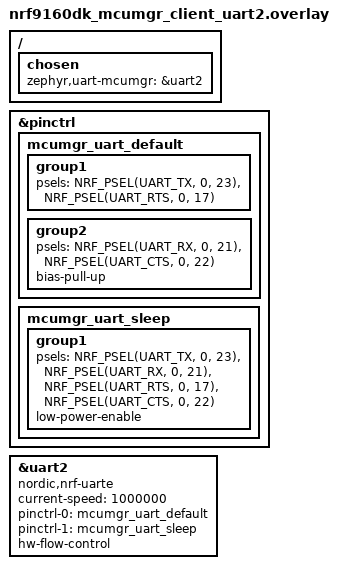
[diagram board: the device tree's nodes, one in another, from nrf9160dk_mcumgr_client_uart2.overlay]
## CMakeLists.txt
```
#
# Copyright (c) 2025 Nordic Semiconductor
#
# SPDX-License-Identifier: LicenseRef-Nordic-5-Clause
#

cmake_minimum_required(VERSION 3.20.0)

find_package(Zephyr REQUIRED HINTS $ENV{ZEPHYR_BASE})
project(nrf_cloud_fota_sample)

# NORDIC SDK APP START
target_sources(app PRIVATE src/main.c)
# NORDIC SDK APP END
```

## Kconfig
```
#
# Copyright (c) 2025 Nordic Semiconductor ASA
#
# SPDX-License-Identifier: LicenseRef-Nordic-5-Clause
#

menu "nRF Cloud CoAP FOTA Sample"

config COAP_FOTA_JOB_CHECK_RATE_MINUTES
	int "Rate (minutes) at which this sample will check for FOTA updates"
	range 1 10080
	default 15

config COAP_FOTA_LTE_LED_NUM
	int "LED number to use for LTE connection status"
	default 0

config COAP_FOTA_BUTTON_EVT_NUM
	int "Button number to use for device interactions"
	default 1

module = NRF_CLOUD_COAP_FOTA_SAMPLE
module-str = nRF Cloud CoAP FOTA Sample
source "${ZEPHYR_BASE}/subsys/logging/Kconfig.template.log_config"

endmenu
menu "Zephyr Kernel"
source "Kconfig.zephyr"
endmenu
```

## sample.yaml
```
sample:
  name: nRF Cloud CoAP FOTA
tests:
  sample.cellular.nrf_cloud_coap_fota:
    sysbuild: true
    build_only: true
    integration_platforms:
      - nrf9151dk/nrf9151/ns
      - thingy91x/nrf9151/ns
    platform_allow:
      - nrf9151dk/nrf9151/ns
      - thingy91x/nrf9151/ns
    tags:
      - ci_build
      - sysbuild
      - ci_samples_cellular
  sample.cellular.nrf_cloud_coap_fota_delta_modem_update:
    sysbuild: true
    build_only: true
    integration_platforms:
      - nrf9151dk/nrf9151/ns
      - thingy91x/nrf9151/ns
    platform_allow:
      - nrf9151dk/nrf9151/ns
      - thingy91x/nrf9151/ns
    tags:
      - ci_build
      - sysbuild
      - ci_samples_cellular
    extra_args:
      - EXTRA_CONF_FILE=delta_modem_fota.conf
```

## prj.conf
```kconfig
# TF-M config
CONFIG_TFM_PROFILE_TYPE_MINIMAL=y

# Sample
CONFIG_NRF_CLOUD_COAP_FOTA_SAMPLE_LOG_LEVEL_INF=y

# nRF Cloud CoAP
CONFIG_NRF_CLOUD=y
CONFIG_NRF_CLOUD_COAP=y
CONFIG_NRF_CLOUD_COAP_DOWNLOADS=y
CONFIG_NRF_CLOUD_COAP_MAX_USER_OPTIONS=2
CONFIG_NRF_CLOUD_CHECK_CREDENTIALS=y

# CoAP Client
CONFIG_COAP_CLIENT_BLOCK_SIZE=1024
CONFIG_COAP_CLIENT_STACK_SIZE=6144
CONFIG_COAP_CLIENT_THREAD_PRIORITY=0
CONFIG_COAP_CLIENT_MAX_EXTRA_OPTIONS=3
CONFIG_COAP_CLIENT_MAX_PATH_LENGTH=400
CONFIG_COAP_EXTENDED_OPTIONS_LEN_VALUE=192

# Networking
CONFIG_NETWORKING=y
CONFIG_NET_SOCKETS=y
CONFIG_NET_SOCKETS_OFFLOAD=y

# Enable LTE Connectivity using Connection Manager
CONFIG_NET_IPV4=y
CONFIG_NET_IPV6=y
CONFIG_NET_IPV6_NBR_CACHE=n
CONFIG_NET_IPV6_MLD=n
CONFIG_NET_CONNECTION_MANAGER=y
CONFIG_NRF_MODEM_LIB=y
CONFIG_NRF_MODEM_LIB_NET_IF=y
CONFIG_NRF_MODEM_LIB_NET_IF_AUTO_DOWN=y
CONFIG_NRF_MODEM_LIB_NET_IF_DOWN_DEFAULT_LTE_DISCONNECT=y
CONFIG_NET_CONNECTION_MANAGER_MONITOR_STACK_SIZE=1024
CONFIG_NET_MGMT_EVENT_STACK_SIZE=2048

# FOTA
CONFIG_MEMFAULT=y
CONFIG_MEMFAULT_USE_NRF_CLOUD_COAP=y
CONFIG_MEMFAULT_HTTP_ENABLE=n
CONFIG_MEMFAULT_ZEPHYR_FOTA_BACKEND_NCS=y
CONFIG_MEMFAULT_NCS_FW_VERSION_STATIC=y
CONFIG_NRF_CLOUD_FOTA=y

# Implement memfault_fota_download_callback() to power off LTE before reboot
CONFIG_MEMFAULT_FOTA_DOWNLOAD_CALLBACK_CUSTOM=y

# Ensure Memfault device id matches nRF Cloud client id
CONFIG_MEMFAULT_NCS_DEVICE_ID_HW_ID=y
CONFIG_HW_ID_LIBRARY_SOURCE_UUID=y

# FOTA download
CONFIG_FOTA_DOWNLOAD=y
CONFIG_FOTA_DOWNLOAD_PROGRESS_EVT=y
CONFIG_DFU_TARGET=y
CONFIG_DOWNLOADER=y
CONFIG_DOWNLOADER_STACK_SIZE=3072
CONFIG_DOWNLOADER_MAX_FILENAME_SIZE=400

# MCUBOOT
CONFIG_BOOTLOADER_MCUBOOT=y
CONFIG_IMG_MANAGER=y
CONFIG_STREAM_FLASH=y
CONFIG_MCUBOOT_IMG_MANAGER=y
CONFIG_IMG_ERASE_PROGRESSIVELY=y
CONFIG_SECURE_BOOT=y

# Settings
CONFIG_FLASH=y
CONFIG_FLASH_PAGE_LAYOUT=y
CONFIG_FLASH_MAP=y
CONFIG_FCB=y
CONFIG_SETTINGS=y
CONFIG_SETTINGS_FCB=y
CONFIG_MPU_ALLOW_FLASH_WRITE=y

# Button/LED support
CONFIG_DK_LIBRARY=y

# LTE Link
CONFIG_LTE_LINK_CONTROL=y

# AT shell
CONFIG_SHELL=y
CONFIG_SHELL_STACK_SIZE=2560
CONFIG_AT_SHELL=y
CONFIG_AT_SHELL_CMD_MODE=y
CONFIG_AT_MONITOR_HEAP_SIZE=4096

# Modem info
CONFIG_MODEM_INFO=y
CONFIG_MODEM_INFO_ADD_DEVICE=y
CONFIG_MODEM_INFO_ADD_NETWORK=y
CONFIG_MODEM_INFO_ADD_SIM=y
CONFIG_MODEM_INFO_ADD_SIM_ICCID=y
CONFIG_MODEM_INFO_ADD_SIM_IMSI=y

# System
CONFIG_HEAP_MEM_POOL_SIZE=12288
CONFIG_MAIN_STACK_SIZE=3072
CONFIG_SYSTEM_WORKQUEUE_STACK_SIZE=2048
CONFIG_ASSERT=y
CONFIG_REBOOT=y
CONFIG_FPU=y
CONFIG_PICOLIBC_IO_FLOAT=y
CONFIG_EVENTS=y
CONFIG_POSIX_API=y

# Logging
CONFIG_LOG=y
CONFIG_LOG_MODE_IMMEDIATE=y
CONFIG_UART_INTERRUPT_DRIVEN=y

# Modem key management
CONFIG_MODEM_KEY_MGMT=y
CONFIG_MODEM_JWT=y
CONFIG_NRF_CLOUD_SEC_TAG=16842753

CONFIG_LTE_LC_PSM_MODULE=y
CONFIG_LTE_LINK_CONTROL=y

# nRF Cloud shadow updates use cJSON which serializes float/double values via
# snprintf("%g", ...). Without this, floats render as "*float*" in the JSON
# string, causing nRF Cloud to reject shadow PATCHes with "Malformed JSON".
CONFIG_CBPRINTF_FP_SUPPORT=y
```

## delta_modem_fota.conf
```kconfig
#
# Copyright (c) 2025 Nordic Semiconductor ASA
#
# SPDX-License-Identifier: LicenseRef-Nordic-5-Clause
#
# Overlay for enabling delta modem FOTA.
# See https://docs.nrfcloud.com/docs/mcu/nrf-modem-fota for full setup instructions.

CONFIG_MEMFAULT_FOTA_MODEM_UPDATE=y

# Not required if the modem firmware project key is set at runtime from the nRF Cloud device shadow via the "memfaultModemKey" control.
# Uncomment to configure the project key at build time.
# CONFIG_MEMFAULT_FOTA_MODEM_PROJECT_KEY="YOUR_MODEM_PROJECT_KEY"
```

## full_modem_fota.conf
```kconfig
#
# Copyright (c) 2025 Nordic Semiconductor ASA
#
# SPDX-License-Identifier: LicenseRef-Nordic-5-Clause
#

# Decrease buffer to make it work with minimal TF-M.
CONFIG_NRF_CLOUD_FOTA_FULL_MODEM_UPDATE_BUF_SIZE=512
CONFIG_TFM_LOG_LEVEL_SILENCE=y

# Full Modem FOTA
CONFIG_NRF_CLOUD_FOTA_FULL_MODEM_UPDATE=y
CONFIG_SPI=y
CONFIG_SPI_NOR=y
CONFIG_SPI_NOR_FLASH_LAYOUT_PAGE_SIZE=4096

# FMFU requires additional heap space.
# If the heap is too small, a boot loop can occur when the full modem image is installed.
CONFIG_HEAP_MEM_POOL_SIZE=47250

CONFIG_COAP_FOTA_JOB_CHECK_RATE_MINUTES=1
CONFIG_IMG_ERASE_PROGRESSIVELY=n
CONFIG_SPI_NOR_SFDP_MINIMAL=n
CONFIG_SPI_NOR_SFDP_DEVICETREE=y
```

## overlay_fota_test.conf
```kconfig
#
# Copyright (c) 2025 Nordic Semiconductor ASA
#
# SPDX-License-Identifier: LicenseRef-Nordic-5-Clause
#

# Build with this overlay to produce an application with a different version string.
# The verion string is printed on startup.
CONFIG_NRF_CLOUD_FOTA_SAMPLE_VERSION="v1.0.0-FOTA-TEST"
```

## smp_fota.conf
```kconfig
#
# Copyright (c) 2025 Nordic Semiconductor ASA
#
# SPDX-License-Identifier: LicenseRef-Nordic-5-Clause
#
CONFIG_NRF_CLOUD_FOTA_SMP=y
CONFIG_NRF_MCUMGR_SMP_CLIENT=y
CONFIG_MCUMGR_GRP_IMG=y
CONFIG_MCUMGR_GRP_OS=y
CONFIG_UART_MCUMGR=y
CONFIG_MCUMGR_TRANSPORT_UART=y
CONFIG_UART_MCUMGR_RX_BUF_COUNT=4
CONFIG_SMP_CMD_RETRY_TIME=1000

# Enable MCUboot util library
CONFIG_MCUBOOT_IMG_MANAGER=y
CONFIG_DFU_TARGET_SMP=y
```

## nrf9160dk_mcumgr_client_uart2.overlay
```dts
/*
 * Copyright (c) 2025 Nordic Semiconductor ASA
 *
 * SPDX-License-Identifier: LicenseRef-Nordic-5-Clause
 */

/* Generic PIN definition for UART2 or UART1 to nRF52840  */
&pinctrl {
	mcumgr_uart_default: mcumgr_uart_default {
		group1 {
			psels = <NRF_PSEL(UART_TX, 0, 23)>,
				<NRF_PSEL(UART_RTS, 0, 17)>;
			};

		group2 {
			psels = <NRF_PSEL(UART_RX, 0, 21)>,
				<NRF_PSEL(UART_CTS, 0, 22)>;
				bias-pull-up;
		};
	};

	mcumgr_uart_sleep: mcumgr_uart_sleep {
		group1 {
			psels = <NRF_PSEL(UART_TX, 0, 23)>,
				<NRF_PSEL(UART_RX, 0, 21)>,
				<NRF_PSEL(UART_RTS, 0, 17)>,
				<NRF_PSEL(UART_CTS, 0, 22)>;
				low-power-enable;
		};
	};
};

&uart2 {
	compatible = "nordic,nrf-uarte";
	current-speed = <1000000>;
	status = "okay";
	pinctrl-0 = <&mcumgr_uart_default>;
	pinctrl-1 = <&mcumgr_uart_sleep>;
	pinctrl-names = "default", "sleep";
	hw-flow-control;
};

/ {
	chosen {
		zephyr,uart-mcumgr = &uart2;
	};
};
```

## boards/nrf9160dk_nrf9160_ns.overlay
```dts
/*
 * Copyright (c) 2025 Nordic Semiconductor ASA
 *
 * SPDX-License-Identifier: LicenseRef-Nordic-5-Clause
 */

/ {
	chosen {
		nordic,fmfu-storage-partition = &fmfu_storage_partition;
	};
};

#include <samples/cellular/nrf91_immutable_bootloader_partitions.dtsi>

/* External flash device is disabled by default */
&mx25r64 {
	status = "okay";

	partitions {
		compatible = "fixed-partitions";
		#address-cells = <1>;
		#size-cells = <1>;

		fmfu_storage_partition: partition@0 {
			label = "fmfu_storage";
			reg = <0x00000000 0x400000>;
		};
	};
};

#include <samples/cellular/nrf91_sram_partitions.dtsi>
```

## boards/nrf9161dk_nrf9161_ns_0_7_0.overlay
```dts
/*
 * Copyright (c) 2025 Nordic Semiconductor ASA
 *
 * SPDX-License-Identifier: LicenseRef-Nordic-5-Clause
 */

/delete-node/ &gd25wb256;

/ {
	chosen {
		nordic,pm-ext-flash = &gd25lb256;
	};
};

&gd25lb256 {
	status = "okay";
};
```

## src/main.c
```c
/*
 * Copyright (c) 2025 Nordic Semiconductor ASA
 *
 * SPDX-License-Identifier: LicenseRef-Nordic-5-Clause
 */

#include <zephyr/kernel.h>
#include <zephyr/settings/settings.h>
#include <zephyr/sys/reboot.h>
#include <zephyr/logging/log.h>
#include <zephyr/logging/log_ctrl.h>
#include <zephyr/net/conn_mgr_connectivity.h>
#include <nrf_modem_at.h>
#include <modem/nrf_modem_lib.h>
#include <modem/lte_lc.h>
#include <modem/modem_info.h>
#include <net/nrf_cloud.h>
#include <net/nrf_cloud_fota_poll.h>
#include <net/nrf_cloud_defs.h>
#include <net/nrf_cloud_coap.h>
#include <net/fota_download.h>
#include <date_time.h>

#include <dk_buttons_and_leds.h>
#ifdef CONFIG_NRF_CLOUD_FOTA_SMP
#include "smp_reset.h"
#endif

#define COAP_SHADOW_MAX_SIZE 512

#include <app_version.h>

LOG_MODULE_REGISTER(nrf_cloud_coap_fota_sample, CONFIG_NRF_CLOUD_COAP_FOTA_SAMPLE_LOG_LEVEL);

#define BTN_NUM		       CONFIG_COAP_FOTA_BUTTON_EVT_NUM
#define LTE_LED_NUM	       CONFIG_COAP_FOTA_LTE_LED_NUM
#define FOTA_CFG_INTERVAL "fotaInterval"
#define INTERVAL_MINUTES_MAX   10080
#define REBOOT_DELAY_REQUIRED 5
#define REBOOT_DELAY_SUCCESS 10
#define REBOOT_DELAY_ERROR 30
#define LED_ON 1
#define LED_OFF 0


/* The interval (in minutes) at which to check for FOTA jobs */
static uint32_t fota_check_rate = CONFIG_COAP_FOTA_JOB_CHECK_RATE_MINUTES;

/* Network states */
#define NETWORK_UP BIT(0)
#define EVENT_MASK (NET_EVENT_L4_CONNECTED | NET_EVENT_L4_DISCONNECTED)

/* Semaphore to indicate a button has been pressed */
static K_EVENT_DEFINE(button_press_event);
#define BUTTON_PRESSED BIT(0)

/* Connection event */
static K_EVENT_DEFINE(connection_events);

/* nRF Cloud device ID */
static char device_id[NRF_CLOUD_CLIENT_ID_MAX_LEN + 1];

/* Modem info */
static struct modem_param_info mdm_param;

static void sample_reboot(enum nrf_cloud_fota_reboot_status status);

/* FOTA support context */
static struct nrf_cloud_fota_poll_ctx fota_ctx = {
	.device_id = device_id,
	.reboot_fn = sample_reboot,
#ifdef CONFIG_NRF_CLOUD_FOTA_SMP
	.smp_reset_cb = nrf52840_reset_api
#endif
};

static void modem_time_wait(void)
{
	int err = 0;
	char time_buf[64];

	LOG_INF("Waiting for modem to acquire network time...");

	do {
		k_sleep(K_SECONDS(3));

		err = nrf_modem_at_cmd(time_buf, sizeof(time_buf), "AT%%CCLK?");
		if (err) {
			LOG_DBG("AT Clock Command Error %d... Retrying in 3 seconds.", err);
		}
	} while (err != 0);

	LOG_INF("Network time obtained");
}

static void get_modem_info(void)
{
	int err = modem_info_params_get(&mdm_param);

	if (err) {
		LOG_WRN("Unable to obtain modem info, error: %d", err);
	}
}

static void send_device_status(void)
{
	int err;
	/* Enable FOTA for bootloader, modem, application and SMP (if enabled) */
	struct nrf_cloud_svc_info_fota fota = {
		.bootloader = 1,
		.modem = 1,
		.application = 1,
		.modem_full = fota_ctx.full_modem_fota_supported,
		.smp = IS_ENABLED(CONFIG_NRF_CLOUD_FOTA_SMP)
	};

	struct nrf_cloud_svc_info svc_inf = {
		.fota = &fota,
	};

	struct nrf_cloud_modem_info mdm_inf = {
		/* Include all available modem info */
		.device = NRF_CLOUD_INFO_SET,
		.network = NRF_CLOUD_INFO_SET,
		.sim = NRF_CLOUD_INFO_SET,
		/* Use the modem info already obtained */
		.mpi = &mdm_param,
		/* Include the application version */
		.application_version = APP_VERSION_STRING
	};

	struct nrf_cloud_device_status dev_status = {
		.modem = &mdm_inf,
		.svc = &svc_inf,
		.conn_inf = NRF_CLOUD_INFO_SET
	};

	LOG_INF("Sending device status...");
	err = nrf_cloud_coap_shadow_device_status_update(&dev_status);
	if (err) {
		LOG_ERR("Failed to send device status, FOTA not enabled; error: %d", err);
	} else {
		LOG_INF("FOTA enabled in device shadow");
	}
}

static bool process_desired_check_rate(long desired_check_rate)
{
		if (desired_check_rate > INTERVAL_MINUTES_MAX) {
			LOG_INF("Desired interval exceeds max value, setting to %d",
				INTERVAL_MINUTES_MAX);
			desired_check_rate = INTERVAL_MINUTES_MAX;
		} else if (desired_check_rate <= 0) {
			LOG_INF("Desired interval must be greater than zero, setting to %d",
				CONFIG_COAP_FOTA_JOB_CHECK_RATE_MIN);
			desired_check_rate = CONFIG_COAP_FOTA_JOB_CHECK_RATE_MIN;
		}
		/* Use the desired value */
		fota_check_rate = (uint32_t)desired_check_rate;
		/* Update the reported value if changed */
		return (fota_check_rate != desired_check_rate);
}

int shadow_support_coap_obj_send(struct nrf_cloud_obj *const shadow_obj, const bool reported)
{
	/* Encode the data for the cloud */
	int err = nrf_cloud_obj_cloud_encode(shadow_obj);

	/* Free the object */
	(void)nrf_cloud_obj_free(shadow_obj);

	if (!err) {
		/* Send the encoded data */
		if (!reported) {
			err = nrf_cloud_coap_shadow_desired_update(shadow_obj->encoded_data.ptr);
		} else {
			err = nrf_cloud_coap_shadow_state_update(shadow_obj->encoded_data.ptr);
		}
	} else {
		LOG_ERR("Failed to encode cloud data, err: %d", err);
		return err;
	}

	/* Free the encoded data */
	(void)nrf_cloud_obj_cloud_encoded_free(shadow_obj);

	return err;
}

static void send_initial_config(void)
{
	NRF_CLOUD_OBJ_JSON_DEFINE(root_obj);
	NRF_CLOUD_OBJ_JSON_DEFINE(cfg_obj);
	int err;

	err = nrf_cloud_obj_init(&root_obj);
	if (err) {
		LOG_ERR("Failed to initialize root object: %d", err);
		goto cleanup;
	}

	err = nrf_cloud_obj_init(&cfg_obj);
	if (err) {
		LOG_ERR("Failed to initialize config object: %d", err);
		(void)nrf_cloud_obj_free(&root_obj);
		goto cleanup;
	}

	/* Create the config object */
	err = nrf_cloud_obj_num_add(&cfg_obj, FOTA_CFG_INTERVAL,
				    (double)fota_check_rate, false);
	if (err) {
		LOG_ERR("Failed to add reported FOTA interval, error: %d", err);
		goto cleanup;
	}

	/* Add the config object to the root object */
	err = nrf_cloud_obj_object_add(&root_obj, NRF_CLOUD_JSON_KEY_CFG, &cfg_obj, false);
	if (err) {
		LOG_ERR("Failed to add config object to root object: %d", err);
		goto cleanup;
	}

	/* Send the initial config */
	err = shadow_support_coap_obj_send(&root_obj, true);
	if (err) {
		LOG_ERR("Failed to send initial config, error: %d", err);
	} else {
		LOG_INF("Initial config sent");
	}
cleanup:
	(void)nrf_cloud_obj_free(&cfg_obj);
	(void)nrf_cloud_obj_free(&root_obj);
}

static void check_config(void)
{

	/* Ensure the reported section gets sent once */
	static bool reported_sent;
	/* Only request full shadow the first time */
	static bool request_delta;
	char buf[COAP_SHADOW_MAX_SIZE] = {0};
	size_t buf_len = sizeof(buf);
	double desired_check_rate = 0;
	bool update_reported = false;
	struct nrf_cloud_data in_data = {
		.ptr = buf
	};
	struct nrf_cloud_obj delta_obj = {0};
	int err;

	LOG_INF("Checking for shadow delta...");
	err = nrf_cloud_coap_shadow_get(buf, &buf_len, false, COAP_CONTENT_FORMAT_APP_JSON);
	if (err == -EACCES) {
		LOG_DBG("Not connected yet.");
		goto exit;
	} else if (err) {
		LOG_ERR("Failed to request shadow delta: %d", err);
		goto exit;
	}
	LOG_DBG("Shadow: len:%zd, %s", strnlen(buf, buf_len), buf);
	request_delta = true;
	in_data.len = buf_len;

	if (strnlen(buf, buf_len) == 0) {
		LOG_DBG("No shadow delta available");
		goto exit;
	}

	/* Convert string into nrf_cloud_obj */
	err = nrf_cloud_coap_shadow_delta_process(&in_data, &delta_obj);
	if (err < 0) {
		LOG_ERR("Failed to process shadow delta, err: %d", err);
		goto exit;
	} else if (err == 0) {
		/* No application specific delta data */
		goto exit;
	}

	NRF_CLOUD_OBJ_JSON_DEFINE(cfg_obj);

	/* Get the config object */
	err = nrf_cloud_obj_object_detach(&delta_obj, NRF_CLOUD_JSON_KEY_CFG, &cfg_obj);
	if (err == -ENODEV) {
		/* No config in the delta */
		goto exit;
	}

	/* Process incoming config */
	err = nrf_cloud_obj_num_get(&cfg_obj, FOTA_CFG_INTERVAL, &desired_check_rate);
	if (err) {
		LOG_ERR("Failed to get desired FOTA interval, error: %d", err);
	} else {
		LOG_INF("Desired interval: %lf", desired_check_rate);
		update_reported = process_desired_check_rate((long)desired_check_rate);
	}

	/* Create config object for response */
	/* Note: this is simpler than trying to handle unsupported entries directly. */
	nrf_cloud_obj_free(&cfg_obj);
	nrf_cloud_obj_init(&cfg_obj);
	err = nrf_cloud_obj_num_add(&cfg_obj, FOTA_CFG_INTERVAL,
				    (double)fota_check_rate, false);
	if (err) {
		LOG_ERR("Failed to add reported FOTA interval, error: %d", err);
		goto exit;
	}

	/* Add current config data */
	if (nrf_cloud_obj_object_add(&delta_obj, NRF_CLOUD_JSON_KEY_CFG, &cfg_obj, false)) {
		goto exit;
	}

	/* Send Shadow update */
	if (update_reported || !reported_sent) {
		err = shadow_support_coap_obj_send(&delta_obj, update_reported);

		if (err) {
			LOG_ERR("Failed to send updated shadow delta, error: %d", err);
		} else {
			reported_sent = true;
			LOG_INF("Updated shadow delta sent");
		}
	}
exit:
	/* Free the objects */
	nrf_cloud_obj_free(&cfg_obj);
	nrf_cloud_obj_free(&delta_obj);

	/* If the reported section was not sent, send the initial config */
	if (!reported_sent) {
		send_initial_config();
	}
}

static bool cred_check(struct nrf_cloud_credentials_status *const cs)
{
	int ret = 0;

	ret = nrf_cloud_credentials_check(cs);
	if (ret) {
		LOG_ERR("nRF Cloud credentials check failed, error: %d", ret);
		return false;
	}

	/* Since this is a CoAP sample, we only need two credentials:
	 *  - a CA for the TLS connections
	 *  - a private key to sign the JWT
	 */

	if (!cs->ca || !cs->ca_aws || !cs->prv_key) {
		LOG_WRN("Missing required nRF Cloud credential(s) in sec tag %u:", cs->sec_tag);
	}
	if (!cs->ca || !cs->ca_aws) {
		LOG_WRN("\t-CA Cert");
	}
	if (!cs->prv_key) {
		LOG_WRN("\t-Private Key");
	}

	return (cs->ca && cs->ca_aws && cs->prv_key);
}

static void await_credentials(void)
{
	struct nrf_cloud_credentials_status cs;

	while (!cred_check(&cs)) {
		LOG_INF("Waiting for credentials to be installed...");
		LOG_INF("Press the reset button once the credentials are installed");
		k_sleep(K_FOREVER);
	}

	LOG_INF("nRF Cloud credentials detected!");
}

static int set_led(const int state)
{
	int err = dk_set_led(LTE_LED_NUM, state);

	if (err) {
		LOG_ERR("Failed to set LED, error: %d", err);
		return err;
	}
	return 0;
}

static void button_handler(uint32_t button_states, uint32_t has_changed)
{
	if (has_changed & button_states & BIT(BTN_NUM - 1)) {
		LOG_DBG("Button %d pressed", BTN_NUM);
		k_event_post(&button_press_event, BUTTON_PRESSED);
	}
}

static int init_led(void)
{
	int err = dk_leds_init();

	if (err) {
		LOG_ERR("LED init failed, error: %d", err);
		return err;
	}
	(void)set_led(LED_OFF);
	return 0;
}

static int init(void)
{
	int err = 0;
	enum nrf_cloud_fota_type pending_job_type = NRF_CLOUD_FOTA_TYPE__INVALID;

	err = init_led();
	if (err) {
		LOG_ERR("LED initialization failed: %d", err);
		return err;
	}

	err = nrf_modem_lib_init();
	if (err) {
		LOG_ERR("Failed to initialize modem library: 0x%X", err);
		return -EFAULT;
	}

	err = nrf_cloud_fota_poll_init(&fota_ctx);
	if (err) {
		LOG_ERR("FOTA support init failed: %d", err);
		return err;
	}

	/* This function may perform a reboot if a FOTA update is in progress */
	err = nrf_cloud_fota_poll_process_pending(&fota_ctx);
	if (err < 0) {
		LOG_ERR("Failed to process pending FOTA job, error: %d", err);
		return err;
	}
	pending_job_type = (enum nrf_cloud_fota_type)err;

	err = modem_info_init();
	if (err) {
		LOG_WRN("Modem info initialization failed, error: %d", err);
		return err;
	}

	err = modem_info_params_init(&mdm_param);
	if (!err) {
		LOG_INF("Application Name: %s", mdm_param.device.app_name);
		LOG_INF("nRF Connect SDK version: %s", mdm_param.device.app_version);
	} else {
		LOG_WRN("Modem info params initialization failed, error: %d", err);
	}

	err = nrf_cloud_client_id_get(device_id, sizeof(device_id));
	if (err) {
		LOG_ERR("Failed to get device ID, error: %d", err);
		return err;
	}

	err = dk_buttons_init(button_handler);
	if (err) {
		LOG_ERR("Failed to initialize button: error: %d", err);
		return err;
	}

	/* Ensure device has credentials installed before proceeding */
	await_credentials();

	/* Initiate Connection */
	LOG_INF("Enabling connectivity...");
	conn_mgr_all_if_connect(true);
	k_event_wait(&connection_events, NETWORK_UP, false, K_FOREVER);

	/* Now that the device is connected to the network, get the modem info */
	get_modem_info();

	/* Modem must have valid time/date in order to generate JWTs with
	 * an expiration time
	 */
	modem_time_wait();

	return err;
}

static void sample_reboot(enum nrf_cloud_fota_reboot_status status)
{
	int seconds;

	switch (status) {
	case FOTA_REBOOT_REQUIRED:
		LOG_INF("Rebooting...");
		seconds = REBOOT_DELAY_REQUIRED;
		break;
	case FOTA_REBOOT_SUCCESS:
		seconds = REBOOT_DELAY_SUCCESS;
		LOG_INF("Rebooting in %ds to complete FOTA update...", seconds);
		break;
	case FOTA_REBOOT_SYS_ERROR:
	default:
		seconds = REBOOT_DELAY_ERROR;
		LOG_INF("Rebooting in %ds...", seconds);
	}
	(void)nrf_cloud_coap_disconnect();

	/* We must do this before we reboot, otherwise we might trip LTE boot loop
	 * prevention, and the modem will be temporarily disable itself.
	 */
	(void)lte_lc_power_off();

	LOG_PANIC();
	k_sleep(K_SECONDS(seconds));
	sys_reboot(SYS_REBOOT_COLD);
}

/* Callback to track network connectivity */
static struct net_mgmt_event_callback l4_callback;
static void l4_event_handler(struct net_mgmt_event_callback *cb, uint64_t event,
			     struct net_if *iface)
{
	if ((event & EVENT_MASK) != event) {
		return;
	}

	if (event == NET_EVENT_L4_CONNECTED) {
		/* Mark network as up. */
		(void)set_led(LED_ON);
		LOG_INF("Connected to LTE");
		k_event_post(&connection_events, NETWORK_UP);
	}

	if (event == NET_EVENT_L4_DISCONNECTED) {
		/* Network is down. */
		(void)set_led(LED_OFF);
		LOG_INF("Network connectivity lost!");
	}
}

/* Start tracking network availability */
static int prepare_network_tracking(void)
{
	net_mgmt_init_event_callback(&l4_callback, l4_event_handler, EVENT_MASK);
	net_mgmt_add_event_callback(&l4_callback);

	return 0;
}

SYS_INIT(prepare_network_tracking, APPLICATION, 0);

/* Apply bounds to requested fota check rate. */
static bool process_desired_fota_check_rate(long desired_rate)
{
	uint32_t previous_rate = fota_check_rate;

	if (desired_rate > INTERVAL_MINUTES_MAX) {
		LOG_WRN("Desired FOTA check rate is %ld, but must be <= %d. Setting to %d",
			desired_rate, INTERVAL_MINUTES_MAX, INTERVAL_MINUTES_MAX);
		desired_rate = INTERVAL_MINUTES_MAX;
	} else if (desired_rate <= 0) {
		LOG_WRN("Desired FOTA check rate is %ld, but must be > 0. Setting to default of %d",
			desired_rate, CONFIG_COAP_FOTA_JOB_CHECK_RATE_MINUTES);
		desired_rate = CONFIG_COAP_FOTA_JOB_CHECK_RATE_MINUTES;
	} else {
		LOG_INF("FOTA check rate set to %ld", desired_rate);
	}

	fota_check_rate = (uint32_t)desired_rate;

	/* Report whether the rate changed */
	return (fota_check_rate != previous_rate);
}

/* Encode a shadow object and write it to nRF Cloud's reported state. */
static int report_shadow_obj(struct nrf_cloud_obj *const shadow_obj)
{
	/* Note this allocates memory for encoded_data that must be freed */
	int err = nrf_cloud_obj_cloud_encode(shadow_obj);

	if (err) {
		LOG_ERR("Failed to encode cloud data, err: %d", err);
		return err;
	}

	err = nrf_cloud_coap_shadow_state_update(shadow_obj->encoded_data.ptr);

	(void)nrf_cloud_obj_cloud_encoded_free(shadow_obj);

	return err;
}

static void send_initial_shadow_config(void)
{
	/* Root of the JSON tree  (i.e.,{ "config": { "fotaInterval": 60 }) */
	NRF_CLOUD_OBJ_JSON_DEFINE(root_obj);

	/* Config section of the JSON tree (i.e., { "fotaInterval": 60 })*/
	NRF_CLOUD_OBJ_JSON_DEFINE(cfg_obj);

	int err = nrf_cloud_obj_init(&root_obj);

	if (err) {
		LOG_ERR("Failed to initialize root object: %d", err);
		goto cleanup;
	}

	err = nrf_cloud_obj_init(&cfg_obj);
	if (err) {
		LOG_ERR("Failed to initialize config object: %d", err);
		(void)nrf_cloud_obj_free(&root_obj);
		goto cleanup;
	}

	/* Create the config object */
	err = nrf_cloud_obj_num_add(&cfg_obj, FOTA_CFG_INTERVAL, (double)fota_check_rate, false);
	if (err) {
		LOG_ERR("Failed to add reported FOTA interval, error: %d", err);
		goto cleanup;
	}

	/* Add the config object to the root object */
	err = nrf_cloud_obj_object_add(&root_obj, NRF_CLOUD_JSON_KEY_CFG, &cfg_obj, false);
	if (err) {
		LOG_ERR("Failed to add config object to root object: %d", err);
		goto cleanup;
	}

	/* Send the initial config with current state */
	err = report_shadow_obj(&root_obj);
	if (err) {
		LOG_ERR("Failed to send initial config, error: %d", err);
	} else {
		LOG_INF("Initial config sent");
	}
cleanup:
	(void)nrf_cloud_obj_free(&cfg_obj);
	(void)nrf_cloud_obj_free(&root_obj);
}

static void check_shadow_config(void)
{
	/* Keep track of whether state has ever been reported */
	static bool state_updated;

	/* Fetch the full desired shadow on the first poll to sync initial state, then request only
	 * deltas afterwards so unchanged values are not fetched on every poll.
	 */
	static bool full_shadow_synced;

	char buf[COAP_SHADOW_MAX_SIZE] = {0};
	size_t buf_len = sizeof(buf);

	struct nrf_cloud_obj delta_obj = {0};

	NRF_CLOUD_OBJ_JSON_DEFINE(cfg_obj);

	LOG_INF("Checking for shadow delta...");
	int err = nrf_cloud_coap_shadow_get(buf, &buf_len, full_shadow_synced,
					    COAP_CONTENT_FORMAT_APP_JSON);
	if (err == -EACCES) {
		LOG_DBG("Not connected yet.");
		goto exit;
	} else if (err) {
		LOG_ERR("Failed to request shadow delta: %d", err);
		goto exit;
	}

	/* On subsequent polls, request only deltas */
	full_shadow_synced = true;

	if (buf_len == 0) {
		LOG_DBG("No shadow delta available");
		goto exit;
	}
	LOG_DBG("Shadow: len:%zu, %s", buf_len, buf);

	struct nrf_cloud_data in_data = {.ptr = buf, .len = buf_len};

	err = nrf_cloud_coap_shadow_delta_process(&in_data, &delta_obj);
	if (err < 0) {
		LOG_ERR("Failed to process shadow delta, err: %d", err);
		goto exit;
	} else if (err == 0) {
		/* No application specific delta data */
		goto exit;
	}

	/* Move the config section to the config object we'll use for reporting */
	err = nrf_cloud_obj_object_detach(&delta_obj, NRF_CLOUD_JSON_KEY_CFG, &cfg_obj);
	if (err == -ENODEV) {
		/* No config in the delta */
		goto exit;
	}

	/* Apply the desired FOTA check interval */
	double desired_check_rate = 0;
	bool update_state = false;

	err = nrf_cloud_obj_num_get(&cfg_obj, FOTA_CFG_INTERVAL, &desired_check_rate);
	if (err) {
		LOG_ERR("Failed to get desired FOTA interval, error: %d", err);
	} else {
		update_state = process_desired_fota_check_rate((long)desired_check_rate);
	}

	/* Rebuild the config with only the supported entries to report the accepted value back. */
	nrf_cloud_obj_free(&cfg_obj);
	nrf_cloud_obj_init(&cfg_obj);
	err = nrf_cloud_obj_num_add(&cfg_obj, FOTA_CFG_INTERVAL, (double)fota_check_rate, false);
	if (err) {
		LOG_ERR("Failed to add reported FOTA interval, error: %d", err);
		goto exit;
	}
	if (nrf_cloud_obj_object_add(&delta_obj, NRF_CLOUD_JSON_KEY_CFG, &cfg_obj, false)) {
		goto exit;
	}

	/* Report the accepted config back to the shadow */
	if (update_state || !state_updated) {
		err = report_shadow_obj(&delta_obj);
		if (err) {
			LOG_ERR("Failed to send updated shadow delta, error: %d", err);
		} else {
			state_updated = true;
			LOG_INF("Updated shadow delta sent");
		}
	}
exit:
	nrf_cloud_obj_free(&cfg_obj);
	nrf_cloud_obj_free(&delta_obj);

	/* Only send the initial config here if it was never sent previously */
	if (!state_updated) {
		send_initial_shadow_config();
	}
}

int main(void)
{
	int err;

	LOG_INF("nRF Cloud CoAP FOTA Sample, version: %s", APP_VERSION_STRING);

	err = init();
	if (err) {
		LOG_ERR("Initialization failed");
		return 0;
	}

	/* log in to nRF Cloud CoAP */
	err = nrf_cloud_coap_init();
	if (err) {
		LOG_ERR("Failed to initialize CoAP client: %d", err);
		return err;
	}
	err = nrf_cloud_coap_connect(NULL);
	if (err) {
		LOG_ERR("Connecting to nRF Cloud failed, error: %d", err);
		return 0;
	}

	/* Send the device status which contains HW/FW version info,
	 * details about the network connection, and FOTA service info.
	 * The FOTA service info is required by nRF Cloud to enable FOTA
	 * for the device.
	 */
	send_device_status();

	while (1) {
		/* Apply shadow settings */
		check_shadow_config();

		/* Query for any pending FOTA jobs. If one is found, download and install
		 * it. This is a blocking operation which can take a long time.
		 * This function is likely to reboot in order to complete the FOTA update.
		 */
		err = nrf_cloud_fota_poll_process(&fota_ctx);
		if (err == -ENOTRECOVERABLE) {
			LOG_ERR("A fatal error occurred during FOTA processing");
			sample_reboot(FOTA_REBOOT_SYS_ERROR);
		} else if (err == -ENOENT) {
			/* A job has finished, check again for another */
			continue;
		}

		/* Check the configuration in the shadow to determine the FOTA check interval */
		check_config();

		LOG_INF("Checking for FOTA job in %d minute(s) or when button %d is pressed",
			fota_check_rate, CONFIG_COAP_FOTA_BUTTON_EVT_NUM);

		/* Wait for the configured duration or a button press */
		k_event_wait(&button_press_event, BUTTON_PRESSED, true, K_MINUTES(fota_check_rate));
	}
}
```

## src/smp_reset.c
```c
/*
 * Copyright (c) 2025 Nordic Semiconductor ASA
 *
 * SPDX-License-Identifier: LicenseRef-Nordic-5-Clause
 */
#include <zephyr/kernel.h>
#include <zephyr/settings/settings.h>
#include <zephyr/logging/log.h>
#include <zephyr/drivers/gpio.h>
#include <zephyr/device.h>
#include <zephyr/devicetree.h>

LOG_MODULE_REGISTER(nrf_cloud_coap_fota_sample_smp, CONFIG_NRF_CLOUD_COAP_FOTA_SAMPLE_LOG_LEVEL);

#define RESET_NODE DT_NODELABEL(nrf52840_reset)
#define HAS_RECOVERY_MODE (DT_NODE_HAS_STATUS(RESET_NODE, okay))

int nrf52840_reset_api(void)
{
	int err;
	const struct gpio_dt_spec reset_pin_spec = GPIO_DT_SPEC_GET(RESET_NODE, gpios);

	if (!device_is_ready(reset_pin_spec.port)) {
		LOG_ERR("Reset device not ready");
		return -EIO;
	}

	/* Configure pin as output and initialize it to inactive state. */
	err = gpio_pin_configure_dt(&reset_pin_spec, GPIO_OUTPUT_INACTIVE);
	if (err) {
		LOG_ERR("Pin configure err: %d", err);
		return err;
	}

	/* Reset the nRF52840 and let it wait until the pin is inactive again
	 * before running to main to ensure that it won't send any data until
	 * the H4 device is setup and ready to receive.
	 */
	err = gpio_pin_set_dt(&reset_pin_spec, 1);
	if (err) {
		LOG_ERR("GPIO Pin set to 1 err: %d", err);
		return err;
	}

	/* Wait for the nRF52840 peripheral to stop sending data.
	 *
	 * It is critical (!) to wait here, so that all bytes
	 * on the lines are received and drained correctly.
	 */
	k_sleep(K_MSEC(10));

	/* We are ready, let the nRF52840 run to main */
	err = gpio_pin_set_dt(&reset_pin_spec, 0);
	if (err) {
		LOG_ERR("GPIO Pin set to 0 err: %d", err);
		return err;
	}

	LOG_DBG("Reset Pin %d", reset_pin_spec.pin);

	return 0;
}
```

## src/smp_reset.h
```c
/*
 * Copyright (c) 2025 Nordic Semiconductor ASA
 *
 * SPDX-License-Identifier: LicenseRef-Nordic-5-Clause
 */

#ifndef _SMP_RESET_H_
#define _SMP_RESET_H_

/**
 * @brief Reset the nRF52840 for SMP FOTA.
 */
int nrf52840_reset_api(void);

#endif /* _SMP_RESET_H_ */
```
